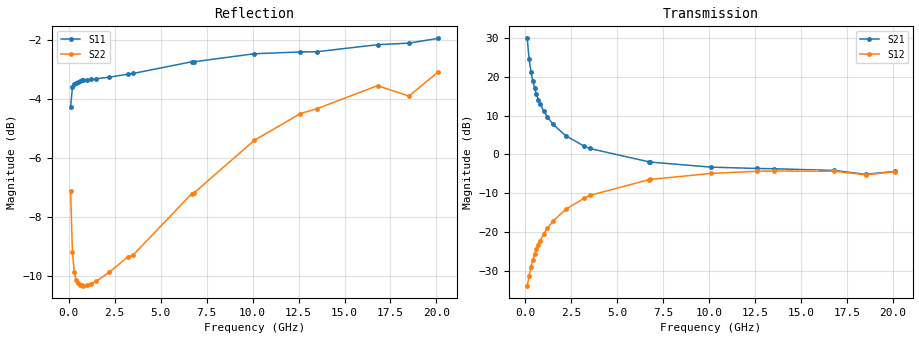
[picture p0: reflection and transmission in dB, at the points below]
!  Infineon Technologies AG
! BFR380L3 , PF131585-7, No.6, Th 09.10.01, soldered on pcb-board, measured with PP GSG850
!  Vce=0.75 V,  Ic=60.0 mA
! Common Emitter S-Parameters:  15. November 2001
#  GHz  S  MA  R  50
! f  S11  S21  S12  S22
! GHz  Mag  Ang  Mag  Ang  Mag  Ang  Mag  Ang
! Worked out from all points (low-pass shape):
!   201 points, 100 MHz to 20.1 GHz, reference 50 ohm
!   highest |S21| = 29.86 dB at 100 MHz (marker M1); lowest = -5.1 dB at 18.5 GHz (marker M2)
!   |S21| within 3 dB of the highest: start of sweep to 157.5 MHz
!   lowest |S11| = -4.3 dB at 100 MHz (marker M3), VSWR 4.14, Z = 13.6 - j17.1 ohm
!   |S11| at or under -10 dB: nowhere
!   |S22| runs from -10.3 to -3.1 dB; largest |S21 - S12| = 31
!   S11 on the Smith chart (normalised r, x): 100 MHz: 0.27, -0.34; 700 MHz: 0.19, +0.03; 3.2 GHz: 0.21, +0.39; 6.7 GHz: 0.27, +0.84; 12.6 GHz: 0.51, +1.59; 20.1 GHz: 1.00, +2.66
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0.1  0.6108 -139.8  31.11 116.7  0.02045 49.3  0.4413 -98.8
0.2  0.6604 -160.9  17.07 101.6  0.02734 54.8  0.3478 -131.9
0.3  0.669 -169.4  11.62 95.3  0.03539 60.2  0.321 -147.2
0.4  0.6728 -174.7  8.797 91.1  0.0435 63.5  0.3116 -155.9
0.5  0.6755 -178.5  7.065 87.9  0.0516 65.8  0.3075 -161.6
0.6  0.6772 178.5  5.909 85.4  0.06039 67.4  0.3054 -165.7
0.7  0.6786 176.0  5.084 82.9  0.0689 68.2  0.305 -168.8
0.8  0.6794 173.8  4.463 80.7  0.0778 68.7  0.3046 -171.4
1  0.6797 169.7  3.597 76.8  0.09518 69.0  0.3051 -175.4
1.2  0.6816 165.9  3.019 73.1  0.1125 68.3  0.3068 -178.4
1.5  0.6832 160.9  2.447 68.0  0.1384 67.1  0.3099 177.7
2.2  0.6874 150.1  1.732 57.0  0.1967 62.3  0.321 170.5
3.2  0.6953 136.0  1.276 43.4  0.2739 54.4  0.3405 161.3
3.5  0.6975 132.0  1.191 39.7  0.2964 51.9  0.3433 159.0
6.7  0.7301 97.5  0.8039 10.7  0.4716 26.8  0.4364 131.9
6.8  0.73 96.5  0.7961 9.9  0.4766 25.9  0.4372 130.9
10.1  0.7533 73.1  0.686 -7.7  0.5692 4.5  0.5374 107.7
12.6  0.7586 60.7  0.6585 -18.6  0.6062 -9.8  0.5964 91.0
13.5  0.7593 57.0  0.6541 -22.4  0.6112 -14.7  0.6077 85.9
16.8  0.7804 45.8  0.621 -33.5  0.6074 -28.9  0.6651 68.8
18.5  0.7852 44.0  0.5543 -41.2  0.5461 -36.8  0.6385 64.8
20.1  0.7999 36.9  0.6033 -44.1  0.5986 -41.5  0.7019 55.0
